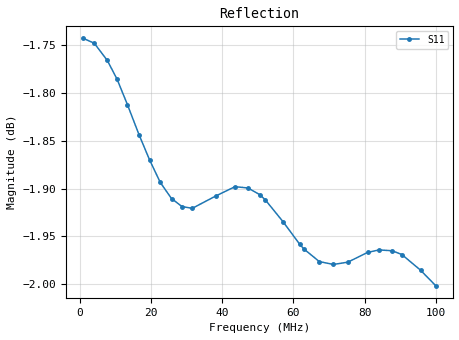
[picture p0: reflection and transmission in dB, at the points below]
# MHz S RI R 50.0
! SimSmith 18.4g
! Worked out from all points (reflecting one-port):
!   1000 points, 1 MHz to 100 MHz, reference 50 ohm
!   lowest |S11| = -2.0 dB at 100 MHz (marker M1), VSWR 8.72, Z = 5.74 + j0.404 ohm
!   phase of S11 starts at -9 deg and turns -892 deg over the sweep
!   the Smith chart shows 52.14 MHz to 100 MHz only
!   S11 on the Smith chart (normalised r, x): 52.14 MHz: 0.16, -0.69; 61.75 MHz: 0.11, +0.14; 71.26 MHz: 0.28, +1.20; 80.87 MHz: 6.09, -4.08; 90.49 MHz: 0.20, -0.89; 100 MHz: 0.11, +0.01
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1  0.8081 -0.1278
4.072072  0.6563 -0.4877
7.738739  0.2839 -0.765
10.51351  -0.0665 -0.8114
13.38739  -0.4139 -0.6982
16.65766  -0.7022 -0.4012
19.63063  -0.8053 -0.0397
22.6036  -0.7341 0.3282
25.77478  -0.4857 0.6389
28.74775  -0.1448 0.7886
31.62162  0.2141 0.7725
38.16216  0.7728 0.2174
43.61261  0.6723 -0.4404
47.27928  0.3246 -0.7351
50.54955  -0.0784 -0.7991
52.13513  -0.2729 -0.7546
57.18919  -0.728 -0.3324
61.74775  -0.7649 0.2281
62.93694  -0.7086 0.3664
67.2973  -0.3154 0.7314
71.26126  0.1708 0.7777
75.32432  0.6005 0.5232
80.87387  0.788 -0.122
84.04505  0.6346 -0.4832
87.71171  0.2696 -0.7506
90.48649  -0.0723 -0.7939
95.73874  -0.6314 -0.4842
100  -0.7941 0.013
